# OpenTallas memory compiler (tools/mem_compiler), ASAP7 abstract view, track-aligned v2 (build_aligned_v2.py)
VERSION 5.7 ;
BUSBITCHARS "[]" ;
DIVIDERCHAR "/" ;
PROPERTYDEFINITIONS
  MACRO width INTEGER ;
  MACRO depth INTEGER ;
  MACRO banks INTEGER ;
END PROPERTYDEFINITIONS
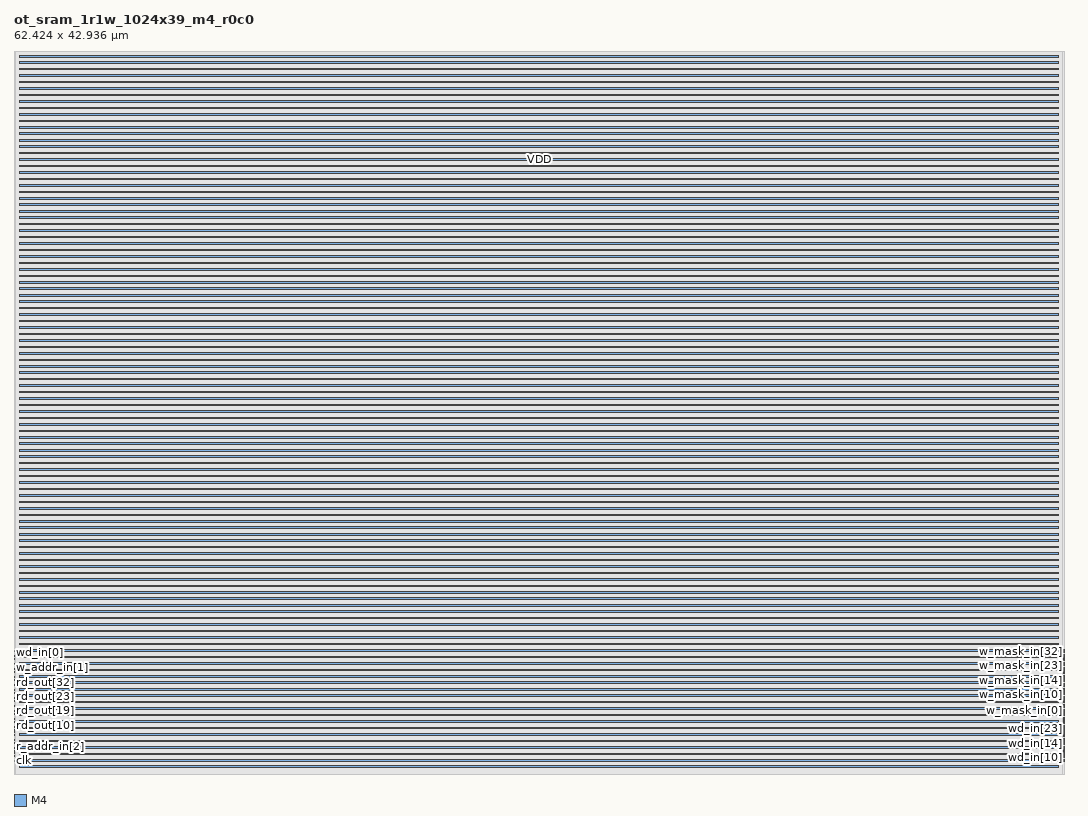
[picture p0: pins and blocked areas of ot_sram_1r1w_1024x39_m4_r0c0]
MACRO ot_sram_1r1w_1024x39_m4_r0c0
  PROPERTY width 39 ;
  PROPERTY depth 1024 ;
  PROPERTY banks 1 ;
  FOREIGN ot_sram_1r1w_1024x39_m4_r0c0 0 0 ;
  SYMMETRY X Y ;
  SIZE 62.424 BY 42.936 ;
  CLASS BLOCK ;
  PIN clk
    DIRECTION INPUT ;
    USE CLOCK ;
    SHAPE ABUTMENT ;
    PORT
      LAYER M4 ;
      RECT 0.000 0.768 0.024 0.792 ;
    END
  END clk
  PIN r_ce_in
    DIRECTION INPUT ;
    USE SIGNAL ;
    SHAPE ABUTMENT ;
    PORT
      LAYER M4 ;
      RECT 0.000 0.864 0.024 0.888 ;
    END
  END r_ce_in
  PIN r_addr_in[0]
    DIRECTION INPUT ;
    USE SIGNAL ;
    SHAPE ABUTMENT ;
    PORT
      LAYER M4 ;
      RECT 0.000 0.960 0.024 0.984 ;
    END
  END r_addr_in[0]
  PIN r_addr_in[1]
    DIRECTION INPUT ;
    USE SIGNAL ;
    SHAPE ABUTMENT ;
    PORT
      LAYER M4 ;
      RECT 0.000 1.056 0.024 1.080 ;
    END
  END r_addr_in[1]
  PIN r_addr_in[2]
    DIRECTION INPUT ;
    USE SIGNAL ;
    SHAPE ABUTMENT ;
    PORT
      LAYER M4 ;
      RECT 0.000 1.152 0.024 1.176 ;
    END
  END r_addr_in[2]
  PIN r_addr_in[3]
    DIRECTION INPUT ;
    USE SIGNAL ;
    SHAPE ABUTMENT ;
    PORT
      LAYER M4 ;
      RECT 0.000 1.248 0.024 1.272 ;
    END
  END r_addr_in[3]
  PIN r_addr_in[4]
    DIRECTION INPUT ;
    USE SIGNAL ;
    SHAPE ABUTMENT ;
    PORT
      LAYER M4 ;
      RECT 0.000 1.344 0.024 1.368 ;
    END
  END r_addr_in[4]
  PIN r_addr_in[5]
    DIRECTION INPUT ;
    USE SIGNAL ;
    SHAPE ABUTMENT ;
    PORT
      LAYER M4 ;
      RECT 0.000 1.440 0.024 1.464 ;
    END
  END r_addr_in[5]
  PIN r_addr_in[6]
    DIRECTION INPUT ;
    USE SIGNAL ;
    SHAPE ABUTMENT ;
    PORT
      LAYER M4 ;
      RECT 0.000 1.536 0.024 1.560 ;
    END
  END r_addr_in[6]
  PIN r_addr_in[7]
    DIRECTION INPUT ;
    USE SIGNAL ;
    SHAPE ABUTMENT ;
    PORT
      LAYER M4 ;
      RECT 0.000 1.632 0.024 1.656 ;
    END
  END r_addr_in[7]
  PIN r_addr_in[8]
    DIRECTION INPUT ;
    USE SIGNAL ;
    SHAPE ABUTMENT ;
    PORT
      LAYER M4 ;
      RECT 0.000 1.728 0.024 1.752 ;
    END
  END r_addr_in[8]
  PIN r_addr_in[9]
    DIRECTION INPUT ;
    USE SIGNAL ;
    SHAPE ABUTMENT ;
    PORT
      LAYER M4 ;
      RECT 0.000 1.824 0.024 1.848 ;
    END
  END r_addr_in[9]
  PIN rd_out[0]
    DIRECTION OUTPUT ;
    USE SIGNAL ;
    SHAPE ABUTMENT ;
    PORT
      LAYER M4 ;
      RECT 0.000 1.920 0.024 1.944 ;
    END
  END rd_out[0]
  PIN rd_out[1]
    DIRECTION OUTPUT ;
    USE SIGNAL ;
    SHAPE ABUTMENT ;
    PORT
      LAYER M4 ;
      RECT 0.000 2.016 0.024 2.040 ;
    END
  END rd_out[1]
  PIN rd_out[2]
    DIRECTION OUTPUT ;
    USE SIGNAL ;
    SHAPE ABUTMENT ;
    PORT
      LAYER M4 ;
      RECT 0.000 2.112 0.024 2.136 ;
    END
  END rd_out[2]
  PIN rd_out[3]
    DIRECTION OUTPUT ;
    USE SIGNAL ;
    SHAPE ABUTMENT ;
    PORT
      LAYER M4 ;
      RECT 0.000 2.208 0.024 2.232 ;
    END
  END rd_out[3]
  PIN rd_out[4]
    DIRECTION OUTPUT ;
    USE SIGNAL ;
    SHAPE ABUTMENT ;
    PORT
      LAYER M4 ;
      RECT 0.000 2.304 0.024 2.328 ;
    END
  END rd_out[4]
  PIN rd_out[5]
    DIRECTION OUTPUT ;
    USE SIGNAL ;
    SHAPE ABUTMENT ;
    PORT
      LAYER M4 ;
      RECT 0.000 2.400 0.024 2.424 ;
    END
  END rd_out[5]
  PIN rd_out[6]
    DIRECTION OUTPUT ;
    USE SIGNAL ;
    SHAPE ABUTMENT ;
    PORT
      LAYER M4 ;
      RECT 0.000 2.496 0.024 2.520 ;
    END
  END rd_out[6]
  PIN rd_out[7]
    DIRECTION OUTPUT ;
    USE SIGNAL ;
    SHAPE ABUTMENT ;
    PORT
      LAYER M4 ;
      RECT 0.000 2.592 0.024 2.616 ;
    END
  END rd_out[7]
  PIN rd_out[8]
    DIRECTION OUTPUT ;
    USE SIGNAL ;
    SHAPE ABUTMENT ;
    PORT
      LAYER M4 ;
      RECT 0.000 2.688 0.024 2.712 ;
    END
  END rd_out[8]
  PIN rd_out[9]
    DIRECTION OUTPUT ;
    USE SIGNAL ;
    SHAPE ABUTMENT ;
    PORT
      LAYER M4 ;
      RECT 0.000 2.784 0.024 2.808 ;
    END
  END rd_out[9]
  PIN rd_out[10]
    DIRECTION OUTPUT ;
    USE SIGNAL ;
    SHAPE ABUTMENT ;
    PORT
      LAYER M4 ;
      RECT 0.000 2.880 0.024 2.904 ;
    END
  END rd_out[10]
  PIN rd_out[11]
    DIRECTION OUTPUT ;
    USE SIGNAL ;
    SHAPE ABUTMENT ;
    PORT
      LAYER M4 ;
      RECT 0.000 2.976 0.024 3.000 ;
    END
  END rd_out[11]
  PIN rd_out[12]
    DIRECTION OUTPUT ;
    USE SIGNAL ;
    SHAPE ABUTMENT ;
    PORT
      LAYER M4 ;
      RECT 0.000 3.072 0.024 3.096 ;
    END
  END rd_out[12]
  PIN rd_out[13]
    DIRECTION OUTPUT ;
    USE SIGNAL ;
    SHAPE ABUTMENT ;
    PORT
      LAYER M4 ;
      RECT 0.000 3.168 0.024 3.192 ;
    END
  END rd_out[13]
  PIN rd_out[14]
    DIRECTION OUTPUT ;
    USE SIGNAL ;
    SHAPE ABUTMENT ;
    PORT
      LAYER M4 ;
      RECT 0.000 3.264 0.024 3.288 ;
    END
  END rd_out[14]
  PIN rd_out[15]
    DIRECTION OUTPUT ;
    USE SIGNAL ;
    SHAPE ABUTMENT ;
    PORT
      LAYER M4 ;
      RECT 0.000 3.360 0.024 3.384 ;
    END
  END rd_out[15]
  PIN rd_out[16]
    DIRECTION OUTPUT ;
    USE SIGNAL ;
    SHAPE ABUTMENT ;
    PORT
      LAYER M4 ;
      RECT 0.000 3.456 0.024 3.480 ;
    END
  END rd_out[16]
  PIN rd_out[17]
    DIRECTION OUTPUT ;
    USE SIGNAL ;
    SHAPE ABUTMENT ;
    PORT
      LAYER M4 ;
      RECT 0.000 3.552 0.024 3.576 ;
    END
  END rd_out[17]
  PIN rd_out[18]
    DIRECTION OUTPUT ;
    USE SIGNAL ;
    SHAPE ABUTMENT ;
    PORT
      LAYER M4 ;
      RECT 0.000 3.648 0.024 3.672 ;
    END
  END rd_out[18]
  PIN rd_out[19]
    DIRECTION OUTPUT ;
    USE SIGNAL ;
    SHAPE ABUTMENT ;
    PORT
      LAYER M4 ;
      RECT 0.000 3.744 0.024 3.768 ;
    END
  END rd_out[19]
  PIN rd_out[20]
    DIRECTION OUTPUT ;
    USE SIGNAL ;
    SHAPE ABUTMENT ;
    PORT
      LAYER M4 ;
      RECT 0.000 3.840 0.024 3.864 ;
    END
  END rd_out[20]
  PIN rd_out[21]
    DIRECTION OUTPUT ;
    USE SIGNAL ;
    SHAPE ABUTMENT ;
    PORT
      LAYER M4 ;
      RECT 0.000 3.936 0.024 3.960 ;
    END
  END rd_out[21]
  PIN rd_out[22]
    DIRECTION OUTPUT ;
    USE SIGNAL ;
    SHAPE ABUTMENT ;
    PORT
      LAYER M4 ;
      RECT 0.000 4.032 0.024 4.056 ;
    END
  END rd_out[22]
  PIN rd_out[23]
    DIRECTION OUTPUT ;
    USE SIGNAL ;
    SHAPE ABUTMENT ;
    PORT
      LAYER M4 ;
      RECT 0.000 4.128 0.024 4.152 ;
    END
  END rd_out[23]
  PIN rd_out[24]
    DIRECTION OUTPUT ;
    USE SIGNAL ;
    SHAPE ABUTMENT ;
    PORT
      LAYER M4 ;
      RECT 0.000 4.224 0.024 4.248 ;
    END
  END rd_out[24]
  PIN rd_out[25]
    DIRECTION OUTPUT ;
    USE SIGNAL ;
    SHAPE ABUTMENT ;
    PORT
      LAYER M4 ;
      RECT 0.000 4.320 0.024 4.344 ;
    END
  END rd_out[25]
  PIN rd_out[26]
    DIRECTION OUTPUT ;
    USE SIGNAL ;
    SHAPE ABUTMENT ;
    PORT
      LAYER M4 ;
      RECT 0.000 4.416 0.024 4.440 ;
    END
  END rd_out[26]
  PIN rd_out[27]
    DIRECTION OUTPUT ;
    USE SIGNAL ;
    SHAPE ABUTMENT ;
    PORT
      LAYER M4 ;
      RECT 0.000 4.512 0.024 4.536 ;
    END
  END rd_out[27]
  PIN rd_out[28]
    DIRECTION OUTPUT ;
    USE SIGNAL ;
    SHAPE ABUTMENT ;
    PORT
      LAYER M4 ;
      RECT 0.000 4.608 0.024 4.632 ;
    END
  END rd_out[28]
  PIN rd_out[29]
    DIRECTION OUTPUT ;
    USE SIGNAL ;
    SHAPE ABUTMENT ;
    PORT
      LAYER M4 ;
      RECT 0.000 4.704 0.024 4.728 ;
    END
  END rd_out[29]
  PIN rd_out[30]
    DIRECTION OUTPUT ;
    USE SIGNAL ;
    SHAPE ABUTMENT ;
    PORT
      LAYER M4 ;
      RECT 0.000 4.800 0.024 4.824 ;
    END
  END rd_out[30]
  PIN rd_out[31]
    DIRECTION OUTPUT ;
    USE SIGNAL ;
    SHAPE ABUTMENT ;
    PORT
      LAYER M4 ;
      RECT 0.000 4.896 0.024 4.920 ;
    END
  END rd_out[31]
  PIN rd_out[32]
    DIRECTION OUTPUT ;
    USE SIGNAL ;
    SHAPE ABUTMENT ;
    PORT
      LAYER M4 ;
      RECT 0.000 4.992 0.024 5.016 ;
    END
  END rd_out[32]
  PIN rd_out[33]
    DIRECTION OUTPUT ;
    USE SIGNAL ;
    SHAPE ABUTMENT ;
    PORT
      LAYER M4 ;
      RECT 0.000 5.088 0.024 5.112 ;
    END
  END rd_out[33]
  PIN rd_out[34]
    DIRECTION OUTPUT ;
    USE SIGNAL ;
    SHAPE ABUTMENT ;
    PORT
      LAYER M4 ;
      RECT 0.000 5.184 0.024 5.208 ;
    END
  END rd_out[34]
  PIN rd_out[35]
    DIRECTION OUTPUT ;
    USE SIGNAL ;
    SHAPE ABUTMENT ;
    PORT
      LAYER M4 ;
      RECT 0.000 5.280 0.024 5.304 ;
    END
  END rd_out[35]
  PIN rd_out[36]
    DIRECTION OUTPUT ;
    USE SIGNAL ;
    SHAPE ABUTMENT ;
    PORT
      LAYER M4 ;
      RECT 0.000 5.376 0.024 5.400 ;
    END
  END rd_out[36]
  PIN rd_out[37]
    DIRECTION OUTPUT ;
    USE SIGNAL ;
    SHAPE ABUTMENT ;
    PORT
      LAYER M4 ;
      RECT 0.000 5.472 0.024 5.496 ;
    END
  END rd_out[37]
  PIN rd_out[38]
    DIRECTION OUTPUT ;
    USE SIGNAL ;
    SHAPE ABUTMENT ;
    PORT
      LAYER M4 ;
      RECT 0.000 5.568 0.024 5.592 ;
    END
  END rd_out[38]
  PIN w_ce_in
    DIRECTION INPUT ;
    USE SIGNAL ;
    SHAPE ABUTMENT ;
    PORT
      LAYER M4 ;
      RECT 0.000 5.664 0.024 5.688 ;
    END
  END w_ce_in
  PIN w_addr_in[0]
    DIRECTION INPUT ;
    USE SIGNAL ;
    SHAPE ABUTMENT ;
    PORT
      LAYER M4 ;
      RECT 0.000 5.760 0.024 5.784 ;
    END
  END w_addr_in[0]
  PIN w_addr_in[1]
    DIRECTION INPUT ;
    USE SIGNAL ;
    SHAPE ABUTMENT ;
    PORT
      LAYER M4 ;
      RECT 0.000 5.856 0.024 5.880 ;
    END
  END w_addr_in[1]
  PIN w_addr_in[2]
    DIRECTION INPUT ;
    USE SIGNAL ;
    SHAPE ABUTMENT ;
    PORT
      LAYER M4 ;
      RECT 0.000 5.952 0.024 5.976 ;
    END
  END w_addr_in[2]
  PIN w_addr_in[3]
    DIRECTION INPUT ;
    USE SIGNAL ;
    SHAPE ABUTMENT ;
    PORT
      LAYER M4 ;
      RECT 0.000 6.048 0.024 6.072 ;
    END
  END w_addr_in[3]
  PIN w_addr_in[4]
    DIRECTION INPUT ;
    USE SIGNAL ;
    SHAPE ABUTMENT ;
    PORT
      LAYER M4 ;
      RECT 0.000 6.144 0.024 6.168 ;
    END
  END w_addr_in[4]
  PIN w_addr_in[5]
    DIRECTION INPUT ;
    USE SIGNAL ;
    SHAPE ABUTMENT ;
    PORT
      LAYER M4 ;
      RECT 0.000 6.240 0.024 6.264 ;
    END
  END w_addr_in[5]
  PIN w_addr_in[6]
    DIRECTION INPUT ;
    USE SIGNAL ;
    SHAPE ABUTMENT ;
    PORT
      LAYER M4 ;
      RECT 0.000 6.336 0.024 6.360 ;
    END
  END w_addr_in[6]
  PIN w_addr_in[7]
    DIRECTION INPUT ;
    USE SIGNAL ;
    SHAPE ABUTMENT ;
    PORT
      LAYER M4 ;
      RECT 0.000 6.432 0.024 6.456 ;
    END
  END w_addr_in[7]
  PIN w_addr_in[8]
    DIRECTION INPUT ;
    USE SIGNAL ;
    SHAPE ABUTMENT ;
    PORT
      LAYER M4 ;
      RECT 0.000 6.528 0.024 6.552 ;
    END
  END w_addr_in[8]
  PIN w_addr_in[9]
    DIRECTION INPUT ;
    USE SIGNAL ;
    SHAPE ABUTMENT ;
    PORT
      LAYER M4 ;
      RECT 0.000 6.624 0.024 6.648 ;
    END
  END w_addr_in[9]
  PIN wd_in[0]
    DIRECTION INPUT ;
    USE SIGNAL ;
    SHAPE ABUTMENT ;
    PORT
      LAYER M4 ;
      RECT 0.000 6.720 0.024 6.744 ;
    END
  END wd_in[0]
  PIN wd_in[1]
    DIRECTION INPUT ;
    USE SIGNAL ;
    SHAPE ABUTMENT ;
    PORT
      LAYER M4 ;
      RECT 0.000 6.816 0.024 6.840 ;
    END
  END wd_in[1]
  PIN wd_in[2]
    DIRECTION INPUT ;
    USE SIGNAL ;
    SHAPE ABUTMENT ;
    PORT
      LAYER M4 ;
      RECT 0.000 6.912 0.024 6.936 ;
    END
  END wd_in[2]
  PIN wd_in[3]
    DIRECTION INPUT ;
    USE SIGNAL ;
    SHAPE ABUTMENT ;
    PORT
      LAYER M4 ;
      RECT 0.000 7.008 0.024 7.032 ;
    END
  END wd_in[3]
  PIN wd_in[4]
    DIRECTION INPUT ;
    USE SIGNAL ;
    SHAPE ABUTMENT ;
    PORT
      LAYER M4 ;
      RECT 0.000 7.104 0.024 7.128 ;
    END
  END wd_in[4]
  PIN wd_in[5]
    DIRECTION INPUT ;
    USE SIGNAL ;
    SHAPE ABUTMENT ;
    PORT
      LAYER M4 ;
      RECT 0.000 7.200 0.024 7.224 ;
    END
  END wd_in[5]
  PIN wd_in[6]
    DIRECTION INPUT ;
    USE SIGNAL ;
    SHAPE ABUTMENT ;
    PORT
      LAYER M4 ;
      RECT 0.000 7.296 0.024 7.320 ;
    END
  END wd_in[6]
  PIN wd_in[7]
    DIRECTION INPUT ;
    USE SIGNAL ;
    SHAPE ABUTMENT ;
    PORT
      LAYER M4 ;
      RECT 0.000 7.392 0.024 7.416 ;
    END
  END wd_in[7]
  PIN wd_in[8]
    DIRECTION INPUT ;
    USE SIGNAL ;
    SHAPE ABUTMENT ;
    PORT
      LAYER M4 ;
      RECT 62.400 0.768 62.424 0.792 ;
    END
  END wd_in[8]
  PIN wd_in[9]
    DIRECTION INPUT ;
    USE SIGNAL ;
    SHAPE ABUTMENT ;
    PORT
      LAYER M4 ;
      RECT 62.400 0.864 62.424 0.888 ;
    END
  END wd_in[9]
  PIN wd_in[10]
    DIRECTION INPUT ;
    USE SIGNAL ;
    SHAPE ABUTMENT ;
    PORT
      LAYER M4 ;
      RECT 62.400 0.960 62.424 0.984 ;
    END
  END wd_in[10]
  PIN wd_in[11]
    DIRECTION INPUT ;
    USE SIGNAL ;
    SHAPE ABUTMENT ;
    PORT
      LAYER M4 ;
      RECT 62.400 1.056 62.424 1.080 ;
    END
  END wd_in[11]
  PIN wd_in[12]
    DIRECTION INPUT ;
    USE SIGNAL ;
    SHAPE ABUTMENT ;
    PORT
      LAYER M4 ;
      RECT 62.400 1.152 62.424 1.176 ;
    END
  END wd_in[12]
  PIN wd_in[13]
    DIRECTION INPUT ;
    USE SIGNAL ;
    SHAPE ABUTMENT ;
    PORT
      LAYER M4 ;
      RECT 62.400 1.248 62.424 1.272 ;
    END
  END wd_in[13]
  PIN wd_in[14]
    DIRECTION INPUT ;
    USE SIGNAL ;
    SHAPE ABUTMENT ;
    PORT
      LAYER M4 ;
      RECT 62.400 1.344 62.424 1.368 ;
    END
  END wd_in[14]
  PIN wd_in[15]
    DIRECTION INPUT ;
    USE SIGNAL ;
    SHAPE ABUTMENT ;
    PORT
      LAYER M4 ;
      RECT 62.400 1.440 62.424 1.464 ;
    END
  END wd_in[15]
  PIN wd_in[16]
    DIRECTION INPUT ;
    USE SIGNAL ;
    SHAPE ABUTMENT ;
    PORT
      LAYER M4 ;
      RECT 62.400 1.536 62.424 1.560 ;
    END
  END wd_in[16]
  PIN wd_in[17]
    DIRECTION INPUT ;
    USE SIGNAL ;
    SHAPE ABUTMENT ;
    PORT
      LAYER M4 ;
      RECT 62.400 1.632 62.424 1.656 ;
    END
  END wd_in[17]
  PIN wd_in[18]
    DIRECTION INPUT ;
    USE SIGNAL ;
    SHAPE ABUTMENT ;
    PORT
      LAYER M4 ;
      RECT 62.400 1.728 62.424 1.752 ;
    END
  END wd_in[18]
  PIN wd_in[19]
    DIRECTION INPUT ;
    USE SIGNAL ;
    SHAPE ABUTMENT ;
    PORT
      LAYER M4 ;
      RECT 62.400 1.824 62.424 1.848 ;
    END
  END wd_in[19]
  PIN wd_in[20]
    DIRECTION INPUT ;
    USE SIGNAL ;
    SHAPE ABUTMENT ;
    PORT
      LAYER M4 ;
      RECT 62.400 1.920 62.424 1.944 ;
    END
  END wd_in[20]
  PIN wd_in[21]
    DIRECTION INPUT ;
    USE SIGNAL ;
    SHAPE ABUTMENT ;
    PORT
      LAYER M4 ;
      RECT 62.400 2.016 62.424 2.040 ;
    END
  END wd_in[21]
  PIN wd_in[22]
    DIRECTION INPUT ;
    USE SIGNAL ;
    SHAPE ABUTMENT ;
    PORT
      LAYER M4 ;
      RECT 62.400 2.112 62.424 2.136 ;
    END
  END wd_in[22]
  PIN wd_in[23]
    DIRECTION INPUT ;
    USE SIGNAL ;
    SHAPE ABUTMENT ;
    PORT
      LAYER M4 ;
      RECT 62.400 2.208 62.424 2.232 ;
    END
  END wd_in[23]
  PIN wd_in[24]
    DIRECTION INPUT ;
    USE SIGNAL ;
    SHAPE ABUTMENT ;
    PORT
      LAYER M4 ;
      RECT 62.400 2.304 62.424 2.328 ;
    END
  END wd_in[24]
  PIN wd_in[25]
    DIRECTION INPUT ;
    USE SIGNAL ;
    SHAPE ABUTMENT ;
    PORT
      LAYER M4 ;
      RECT 62.400 2.400 62.424 2.424 ;
    END
  END wd_in[25]
  PIN wd_in[26]
    DIRECTION INPUT ;
    USE SIGNAL ;
    SHAPE ABUTMENT ;
    PORT
      LAYER M4 ;
      RECT 62.400 2.496 62.424 2.520 ;
    END
  END wd_in[26]
  PIN wd_in[27]
    DIRECTION INPUT ;
    USE SIGNAL ;
    SHAPE ABUTMENT ;
    PORT
      LAYER M4 ;
      RECT 62.400 2.592 62.424 2.616 ;
    END
  END wd_in[27]
  PIN wd_in[28]
    DIRECTION INPUT ;
    USE SIGNAL ;
    SHAPE ABUTMENT ;
    PORT
      LAYER M4 ;
      RECT 62.400 2.688 62.424 2.712 ;
    END
  END wd_in[28]
  PIN wd_in[29]
    DIRECTION INPUT ;
    USE SIGNAL ;
    SHAPE ABUTMENT ;
    PORT
      LAYER M4 ;
      RECT 62.400 2.784 62.424 2.808 ;
    END
  END wd_in[29]
  PIN wd_in[30]
    DIRECTION INPUT ;
    USE SIGNAL ;
    SHAPE ABUTMENT ;
    PORT
      LAYER M4 ;
      RECT 62.400 2.880 62.424 2.904 ;
    END
  END wd_in[30]
  PIN wd_in[31]
    DIRECTION INPUT ;
    USE SIGNAL ;
    SHAPE ABUTMENT ;
    PORT
      LAYER M4 ;
      RECT 62.400 2.976 62.424 3.000 ;
    END
  END wd_in[31]
  PIN wd_in[32]
    DIRECTION INPUT ;
    USE SIGNAL ;
    SHAPE ABUTMENT ;
    PORT
      LAYER M4 ;
      RECT 62.400 3.072 62.424 3.096 ;
    END
  END wd_in[32]
  PIN wd_in[33]
    DIRECTION INPUT ;
    USE SIGNAL ;
    SHAPE ABUTMENT ;
    PORT
      LAYER M4 ;
      RECT 62.400 3.168 62.424 3.192 ;
    END
  END wd_in[33]
  PIN wd_in[34]
    DIRECTION INPUT ;
    USE SIGNAL ;
    SHAPE ABUTMENT ;
    PORT
      LAYER M4 ;
      RECT 62.400 3.264 62.424 3.288 ;
    END
  END wd_in[34]
  PIN wd_in[35]
    DIRECTION INPUT ;
    USE SIGNAL ;
    SHAPE ABUTMENT ;
    PORT
      LAYER M4 ;
      RECT 62.400 3.360 62.424 3.384 ;
    END
  END wd_in[35]
  PIN wd_in[36]
    DIRECTION INPUT ;
    USE SIGNAL ;
    SHAPE ABUTMENT ;
    PORT
      LAYER M4 ;
      RECT 62.400 3.456 62.424 3.480 ;
    END
  END wd_in[36]
  PIN wd_in[37]
    DIRECTION INPUT ;
    USE SIGNAL ;
    SHAPE ABUTMENT ;
    PORT
      LAYER M4 ;
      RECT 62.400 3.552 62.424 3.576 ;
    END
  END wd_in[37]
  PIN wd_in[38]
    DIRECTION INPUT ;
    USE SIGNAL ;
    SHAPE ABUTMENT ;
    PORT
      LAYER M4 ;
      RECT 62.400 3.648 62.424 3.672 ;
    END
  END wd_in[38]
  PIN w_mask_in[0]
    DIRECTION INPUT ;
    USE SIGNAL ;
    SHAPE ABUTMENT ;
    PORT
      LAYER M4 ;
      RECT 62.400 3.744 62.424 3.768 ;
    END
  END w_mask_in[0]
  PIN w_mask_in[1]
    DIRECTION INPUT ;
    USE SIGNAL ;
    SHAPE ABUTMENT ;
    PORT
      LAYER M4 ;
      RECT 62.400 3.840 62.424 3.864 ;
    END
  END w_mask_in[1]
  PIN w_mask_in[2]
    DIRECTION INPUT ;
    USE SIGNAL ;
    SHAPE ABUTMENT ;
    PORT
      LAYER M4 ;
      RECT 62.400 3.936 62.424 3.960 ;
    END
  END w_mask_in[2]
  PIN w_mask_in[3]
    DIRECTION INPUT ;
    USE SIGNAL ;
    SHAPE ABUTMENT ;
    PORT
      LAYER M4 ;
      RECT 62.400 4.032 62.424 4.056 ;
    END
  END w_mask_in[3]
  PIN w_mask_in[4]
    DIRECTION INPUT ;
    USE SIGNAL ;
    SHAPE ABUTMENT ;
    PORT
      LAYER M4 ;
      RECT 62.400 4.128 62.424 4.152 ;
    END
  END w_mask_in[4]
  PIN w_mask_in[5]
    DIRECTION INPUT ;
    USE SIGNAL ;
    SHAPE ABUTMENT ;
    PORT
      LAYER M4 ;
      RECT 62.400 4.224 62.424 4.248 ;
    END
  END w_mask_in[5]
  PIN w_mask_in[6]
    DIRECTION INPUT ;
    USE SIGNAL ;
    SHAPE ABUTMENT ;
    PORT
      LAYER M4 ;
      RECT 62.400 4.320 62.424 4.344 ;
    END
  END w_mask_in[6]
  PIN w_mask_in[7]
    DIRECTION INPUT ;
    USE SIGNAL ;
    SHAPE ABUTMENT ;
    PORT
      LAYER M4 ;
      RECT 62.400 4.416 62.424 4.440 ;
    END
  END w_mask_in[7]
  PIN w_mask_in[8]
    DIRECTION INPUT ;
    USE SIGNAL ;
    SHAPE ABUTMENT ;
    PORT
      LAYER M4 ;
      RECT 62.400 4.512 62.424 4.536 ;
    END
  END w_mask_in[8]
  PIN w_mask_in[9]
    DIRECTION INPUT ;
    USE SIGNAL ;
    SHAPE ABUTMENT ;
    PORT
      LAYER M4 ;
      RECT 62.400 4.608 62.424 4.632 ;
    END
  END w_mask_in[9]
  PIN w_mask_in[10]
    DIRECTION INPUT ;
    USE SIGNAL ;
    SHAPE ABUTMENT ;
    PORT
      LAYER M4 ;
      RECT 62.400 4.704 62.424 4.728 ;
    END
  END w_mask_in[10]
  PIN w_mask_in[11]
    DIRECTION INPUT ;
    USE SIGNAL ;
    SHAPE ABUTMENT ;
    PORT
      LAYER M4 ;
      RECT 62.400 4.800 62.424 4.824 ;
    END
  END w_mask_in[11]
  PIN w_mask_in[12]
    DIRECTION INPUT ;
    USE SIGNAL ;
    SHAPE ABUTMENT ;
    PORT
      LAYER M4 ;
      RECT 62.400 4.896 62.424 4.920 ;
    END
  END w_mask_in[12]
  PIN w_mask_in[13]
    DIRECTION INPUT ;
    USE SIGNAL ;
    SHAPE ABUTMENT ;
    PORT
      LAYER M4 ;
      RECT 62.400 4.992 62.424 5.016 ;
    END
  END w_mask_in[13]
  PIN w_mask_in[14]
    DIRECTION INPUT ;
    USE SIGNAL ;
    SHAPE ABUTMENT ;
    PORT
      LAYER M4 ;
      RECT 62.400 5.088 62.424 5.112 ;
    END
  END w_mask_in[14]
  PIN w_mask_in[15]
    DIRECTION INPUT ;
    USE SIGNAL ;
    SHAPE ABUTMENT ;
    PORT
      LAYER M4 ;
      RECT 62.400 5.184 62.424 5.208 ;
    END
  END w_mask_in[15]
  PIN w_mask_in[16]
    DIRECTION INPUT ;
    USE SIGNAL ;
    SHAPE ABUTMENT ;
    PORT
      LAYER M4 ;
      RECT 62.400 5.280 62.424 5.304 ;
    END
  END w_mask_in[16]
  PIN w_mask_in[17]
    DIRECTION INPUT ;
    USE SIGNAL ;
    SHAPE ABUTMENT ;
    PORT
      LAYER M4 ;
      RECT 62.400 5.376 62.424 5.400 ;
    END
  END w_mask_in[17]
  PIN w_mask_in[18]
    DIRECTION INPUT ;
    USE SIGNAL ;
    SHAPE ABUTMENT ;
    PORT
      LAYER M4 ;
      RECT 62.400 5.472 62.424 5.496 ;
    END
  END w_mask_in[18]
  PIN w_mask_in[19]
    DIRECTION INPUT ;
    USE SIGNAL ;
    SHAPE ABUTMENT ;
    PORT
      LAYER M4 ;
      RECT 62.400 5.568 62.424 5.592 ;
    END
  END w_mask_in[19]
  PIN w_mask_in[20]
    DIRECTION INPUT ;
    USE SIGNAL ;
    SHAPE ABUTMENT ;
    PORT
      LAYER M4 ;
      RECT 62.400 5.664 62.424 5.688 ;
    END
  END w_mask_in[20]
  PIN w_mask_in[21]
    DIRECTION INPUT ;
    USE SIGNAL ;
    SHAPE ABUTMENT ;
    PORT
      LAYER M4 ;
      RECT 62.400 5.760 62.424 5.784 ;
    END
  END w_mask_in[21]
  PIN w_mask_in[22]
    DIRECTION INPUT ;
    USE SIGNAL ;
    SHAPE ABUTMENT ;
    PORT
      LAYER M4 ;
      RECT 62.400 5.856 62.424 5.880 ;
    END
  END w_mask_in[22]
  PIN w_mask_in[23]
    DIRECTION INPUT ;
    USE SIGNAL ;
    SHAPE ABUTMENT ;
    PORT
      LAYER M4 ;
      RECT 62.400 5.952 62.424 5.976 ;
    END
  END w_mask_in[23]
  PIN w_mask_in[24]
    DIRECTION INPUT ;
    USE SIGNAL ;
    SHAPE ABUTMENT ;
    PORT
      LAYER M4 ;
      RECT 62.400 6.048 62.424 6.072 ;
    END
  END w_mask_in[24]
  PIN w_mask_in[25]
    DIRECTION INPUT ;
    USE SIGNAL ;
    SHAPE ABUTMENT ;
    PORT
      LAYER M4 ;
      RECT 62.400 6.144 62.424 6.168 ;
    END
  END w_mask_in[25]
  PIN w_mask_in[26]
    DIRECTION INPUT ;
    USE SIGNAL ;
    SHAPE ABUTMENT ;
    PORT
      LAYER M4 ;
      RECT 62.400 6.240 62.424 6.264 ;
    END
  END w_mask_in[26]
  PIN w_mask_in[27]
    DIRECTION INPUT ;
    USE SIGNAL ;
    SHAPE ABUTMENT ;
    PORT
      LAYER M4 ;
      RECT 62.400 6.336 62.424 6.360 ;
    END
  END w_mask_in[27]
  PIN w_mask_in[28]
    DIRECTION INPUT ;
    USE SIGNAL ;
    SHAPE ABUTMENT ;
    PORT
      LAYER M4 ;
      RECT 62.400 6.432 62.424 6.456 ;
    END
  END w_mask_in[28]
  PIN w_mask_in[29]
    DIRECTION INPUT ;
    USE SIGNAL ;
    SHAPE ABUTMENT ;
    PORT
      LAYER M4 ;
      RECT 62.400 6.528 62.424 6.552 ;
    END
  END w_mask_in[29]
  PIN w_mask_in[30]
    DIRECTION INPUT ;
    USE SIGNAL ;
    SHAPE ABUTMENT ;
    PORT
      LAYER M4 ;
      RECT 62.400 6.624 62.424 6.648 ;
    END
  END w_mask_in[30]
  PIN w_mask_in[31]
    DIRECTION INPUT ;
    USE SIGNAL ;
    SHAPE ABUTMENT ;
    PORT
      LAYER M4 ;
      RECT 62.400 6.720 62.424 6.744 ;
    END
  END w_mask_in[31]
  PIN w_mask_in[32]
    DIRECTION INPUT ;
    USE SIGNAL ;
    SHAPE ABUTMENT ;
    PORT
      LAYER M4 ;
      RECT 62.400 6.816 62.424 6.840 ;
    END
  END w_mask_in[32]
  PIN w_mask_in[33]
    DIRECTION INPUT ;
    USE SIGNAL ;
    SHAPE ABUTMENT ;
    PORT
      LAYER M4 ;
      RECT 62.400 6.912 62.424 6.936 ;
    END
  END w_mask_in[33]
  PIN w_mask_in[34]
    DIRECTION INPUT ;
    USE SIGNAL ;
    SHAPE ABUTMENT ;
    PORT
      LAYER M4 ;
      RECT 62.400 7.008 62.424 7.032 ;
    END
  END w_mask_in[34]
  PIN w_mask_in[35]
    DIRECTION INPUT ;
    USE SIGNAL ;
    SHAPE ABUTMENT ;
    PORT
      LAYER M4 ;
      RECT 62.400 7.104 62.424 7.128 ;
    END
  END w_mask_in[35]
  PIN w_mask_in[36]
    DIRECTION INPUT ;
    USE SIGNAL ;
    SHAPE ABUTMENT ;
    PORT
      LAYER M4 ;
      RECT 62.400 7.200 62.424 7.224 ;
    END
  END w_mask_in[36]
  PIN w_mask_in[37]
    DIRECTION INPUT ;
    USE SIGNAL ;
    SHAPE ABUTMENT ;
    PORT
      LAYER M4 ;
      RECT 62.400 7.296 62.424 7.320 ;
    END
  END w_mask_in[37]
  PIN w_mask_in[38]
    DIRECTION INPUT ;
    USE SIGNAL ;
    SHAPE ABUTMENT ;
    PORT
      LAYER M4 ;
      RECT 62.400 7.392 62.424 7.416 ;
    END
  END w_mask_in[38]
  PIN VDD
    DIRECTION INOUT ;
    USE POWER ;
    PORT
      LAYER M4 ;
      RECT 0.300 0.384 62.124 0.480 ;
      RECT 0.300 1.152 62.124 1.248 ;
      RECT 0.300 1.920 62.124 2.016 ;
      RECT 0.300 2.688 62.124 2.784 ;
      RECT 0.300 3.456 62.124 3.552 ;
      RECT 0.300 4.224 62.124 4.320 ;
      RECT 0.300 4.992 62.124 5.088 ;
      RECT 0.300 5.760 62.124 5.856 ;
      RECT 0.300 6.528 62.124 6.624 ;
      RECT 0.300 7.296 62.124 7.392 ;
      RECT 0.300 8.064 62.124 8.160 ;
      RECT 0.300 8.832 62.124 8.928 ;
      RECT 0.300 9.600 62.124 9.696 ;
      RECT 0.300 10.368 62.124 10.464 ;
      RECT 0.300 11.136 62.124 11.232 ;
      RECT 0.300 11.904 62.124 12.000 ;
      RECT 0.300 12.672 62.124 12.768 ;
      RECT 0.300 13.440 62.124 13.536 ;
      RECT 0.300 14.208 62.124 14.304 ;
      RECT 0.300 14.976 62.124 15.072 ;
      RECT 0.300 15.744 62.124 15.840 ;
      RECT 0.300 16.512 62.124 16.608 ;
      RECT 0.300 17.280 62.124 17.376 ;
      RECT 0.300 18.048 62.124 18.144 ;
      RECT 0.300 18.816 62.124 18.912 ;
      RECT 0.300 19.584 62.124 19.680 ;
      RECT 0.300 20.352 62.124 20.448 ;
      RECT 0.300 21.120 62.124 21.216 ;
      RECT 0.300 21.888 62.124 21.984 ;
      RECT 0.300 22.656 62.124 22.752 ;
      RECT 0.300 23.424 62.124 23.520 ;
      RECT 0.300 24.192 62.124 24.288 ;
      RECT 0.300 24.960 62.124 25.056 ;
      RECT 0.300 25.728 62.124 25.824 ;
      RECT 0.300 26.496 62.124 26.592 ;
      RECT 0.300 27.264 62.124 27.360 ;
      RECT 0.300 28.032 62.124 28.128 ;
      RECT 0.300 28.800 62.124 28.896 ;
      RECT 0.300 29.568 62.124 29.664 ;
      RECT 0.300 30.336 62.124 30.432 ;
      RECT 0.300 31.104 62.124 31.200 ;
      RECT 0.300 31.872 62.124 31.968 ;
      RECT 0.300 32.640 62.124 32.736 ;
      RECT 0.300 33.408 62.124 33.504 ;
      RECT 0.300 34.176 62.124 34.272 ;
      RECT 0.300 34.944 62.124 35.040 ;
      RECT 0.300 35.712 62.124 35.808 ;
      RECT 0.300 36.480 62.124 36.576 ;
      RECT 0.300 37.248 62.124 37.344 ;
      RECT 0.300 38.016 62.124 38.112 ;
      RECT 0.300 38.784 62.124 38.880 ;
      RECT 0.300 39.552 62.124 39.648 ;
      RECT 0.300 40.320 62.124 40.416 ;
      RECT 0.300 41.088 62.124 41.184 ;
      RECT 0.300 41.856 62.124 41.952 ;
      RECT 0.300 42.624 62.124 42.720 ;
    END
  END VDD
  PIN VSS
    DIRECTION INOUT ;
    USE GROUND ;
    PORT
      LAYER M4 ;
      RECT 0.300 0.768 62.124 0.864 ;
      RECT 0.300 1.536 62.124 1.632 ;
      RECT 0.300 2.304 62.124 2.400 ;
      RECT 0.300 3.072 62.124 3.168 ;
      RECT 0.300 3.840 62.124 3.936 ;
      RECT 0.300 4.608 62.124 4.704 ;
      RECT 0.300 5.376 62.124 5.472 ;
      RECT 0.300 6.144 62.124 6.240 ;
      RECT 0.300 6.912 62.124 7.008 ;
      RECT 0.300 7.680 62.124 7.776 ;
      RECT 0.300 8.448 62.124 8.544 ;
      RECT 0.300 9.216 62.124 9.312 ;
      RECT 0.300 9.984 62.124 10.080 ;
      RECT 0.300 10.752 62.124 10.848 ;
      RECT 0.300 11.520 62.124 11.616 ;
      RECT 0.300 12.288 62.124 12.384 ;
      RECT 0.300 13.056 62.124 13.152 ;
      RECT 0.300 13.824 62.124 13.920 ;
      RECT 0.300 14.592 62.124 14.688 ;
      RECT 0.300 15.360 62.124 15.456 ;
      RECT 0.300 16.128 62.124 16.224 ;
      RECT 0.300 16.896 62.124 16.992 ;
      RECT 0.300 17.664 62.124 17.760 ;
      RECT 0.300 18.432 62.124 18.528 ;
      RECT 0.300 19.200 62.124 19.296 ;
      RECT 0.300 19.968 62.124 20.064 ;
      RECT 0.300 20.736 62.124 20.832 ;
      RECT 0.300 21.504 62.124 21.600 ;
      RECT 0.300 22.272 62.124 22.368 ;
      RECT 0.300 23.040 62.124 23.136 ;
      RECT 0.300 23.808 62.124 23.904 ;
      RECT 0.300 24.576 62.124 24.672 ;
      RECT 0.300 25.344 62.124 25.440 ;
      RECT 0.300 26.112 62.124 26.208 ;
      RECT 0.300 26.880 62.124 26.976 ;
      RECT 0.300 27.648 62.124 27.744 ;
      RECT 0.300 28.416 62.124 28.512 ;
      RECT 0.300 29.184 62.124 29.280 ;
      RECT 0.300 29.952 62.124 30.048 ;
      RECT 0.300 30.720 62.124 30.816 ;
      RECT 0.300 31.488 62.124 31.584 ;
      RECT 0.300 32.256 62.124 32.352 ;
      RECT 0.300 33.024 62.124 33.120 ;
      RECT 0.300 33.792 62.124 33.888 ;
      RECT 0.300 34.560 62.124 34.656 ;
      RECT 0.300 35.328 62.124 35.424 ;
      RECT 0.300 36.096 62.124 36.192 ;
      RECT 0.300 36.864 62.124 36.960 ;
      RECT 0.300 37.632 62.124 37.728 ;
      RECT 0.300 38.400 62.124 38.496 ;
      RECT 0.300 39.168 62.124 39.264 ;
      RECT 0.300 39.936 62.124 40.032 ;
      RECT 0.300 40.704 62.124 40.800 ;
      RECT 0.300 41.472 62.124 41.568 ;
      RECT 0.300 42.240 62.124 42.336 ;
    END
  END VSS
  OBS
    LAYER M1 ;
    RECT 0 0 62.424 42.936 ;
    LAYER M2 ;
    RECT 0 0 62.424 42.936 ;
    LAYER M3 ;
    RECT 0 0 62.424 42.936 ;
    LAYER M4 ;
    RECT 0.072 0 62.352 42.936 ;
  END
END ot_sram_1r1w_1024x39_m4_r0c0

END LIBRARY
